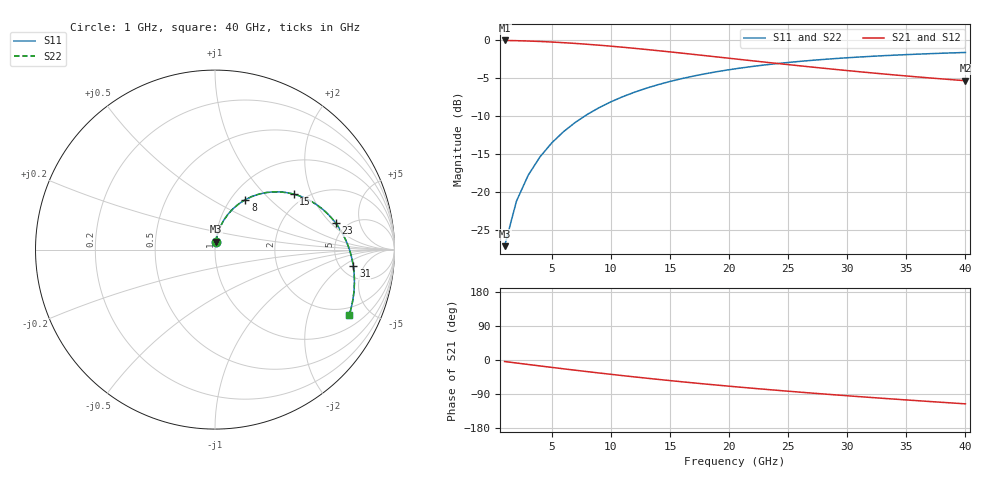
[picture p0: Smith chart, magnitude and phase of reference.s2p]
! circuitRF F0 spike reference -- case A, Palace, hexagon, after 2 AMR iterations (final mesh)
! Palace postpro/port-S.csv, dB/deg -> RI; port 1 excited only; S22 = S11 and S12 = S21 by the mirror symmetry of the geometry about x = 0
# GHz S RI R 50
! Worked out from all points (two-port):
!   40 points, 1 GHz to 40 GHz, reference 50 ohm
!   highest |S21| = -0.02 dB at 1 GHz (marker M1); lowest = -5.3 dB at 40 GHz (marker M2)
!   |S21| within 3 dB of the highest: start of sweep to 23.93 GHz
!   lowest |S11| = -27.1 dB at 1 GHz (marker M3), VSWR 1.09, Z = 50.3 + j4.43 ohm
!   |S11| at or under -10 dB: start of sweep to 7.753 GHz
!   |S22| runs from -27.1 to -1.6 dB; largest |S21 - S12| = 0
!   S11 on the Smith chart (normalised r, x): 1 GHz: 1.01, +0.09; 8 GHz: 1.16, +0.72; 15 GHz: 1.73, +1.50; 23 GHz: 4.05, +2.29; 31 GHz: 6.51, -3.02; 40 GHz: 1.58, -3.72
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1  0.00445 0.044  0.9952 -0.0695  0.9952 -0.0695  0.00445 0.044
2  0.014 0.0862  0.9847 -0.1371  0.9847 -0.1371  0.014 0.0862
3  0.0289 0.1265  0.9681 -0.2028  0.9681 -0.2028  0.0289 0.1265
4  0.0489 0.1642  0.9458 -0.2658  0.9458 -0.2658  0.0489 0.1642
5  0.0736 0.1986  0.9182 -0.3255  0.9182 -0.3255  0.0736 0.1986
6  0.1022 0.2294  0.8859 -0.3815  0.8859 -0.3815  0.1022 0.2294
7  0.1343 0.256  0.8496 -0.4332  0.8496 -0.4332  0.1343 0.256
8  0.1692 0.2783  0.8098 -0.4804  0.8098 -0.4804  0.1692 0.2783
9  0.2061 0.2959  0.7674 -0.5229  0.7674 -0.5229  0.2061 0.2959
11  0.2835 0.3175  0.6769 -0.5937  0.6769 -0.5937  0.2835 0.3175
12  0.3229 0.3216  0.63 -0.6222  0.63 -0.6222  0.3229 0.3216
14  0.4005 0.3173  0.5356 -0.6659  0.5356 -0.6659  0.4005 0.3173
15  0.4379 0.3094  0.4889 -0.6817  0.4889 -0.6817  0.4379 0.3094
18  0.5407 0.2664  0.3545 -0.7085  0.3545 -0.7085  0.5407 0.2664
21  0.6259 0.2011  0.2323 -0.7102  0.2323 -0.7102  0.6259 0.2011
23  0.6718 0.1489  0.1589 -0.7011  0.1589 -0.7011  0.6718 0.1489
25  0.7089 0.092  0.0921 -0.6859  0.0921 -0.6859  0.7089 0.092
27  0.7375 0.032  0.0316 -0.6662  0.0316 -0.6662  0.7375 0.032
31  0.7706 -0.0922  -0.0717 -0.6174  -0.0717 -0.6174  0.7706 -0.0922
34  0.7767 -0.1853  -0.1355 -0.5761  -0.1355 -0.5761  0.7767 -0.1853
37  0.7687 -0.2759  -0.1895 -0.5328  -0.1895 -0.5328  0.7687 -0.2759
40  0.7484 -0.3625  -0.2351 -0.4887  -0.2351 -0.4887  0.7484 -0.3625
